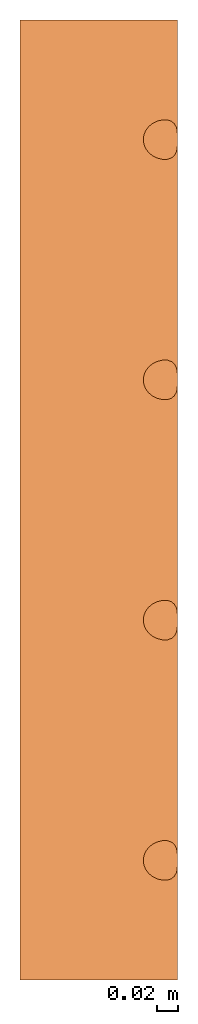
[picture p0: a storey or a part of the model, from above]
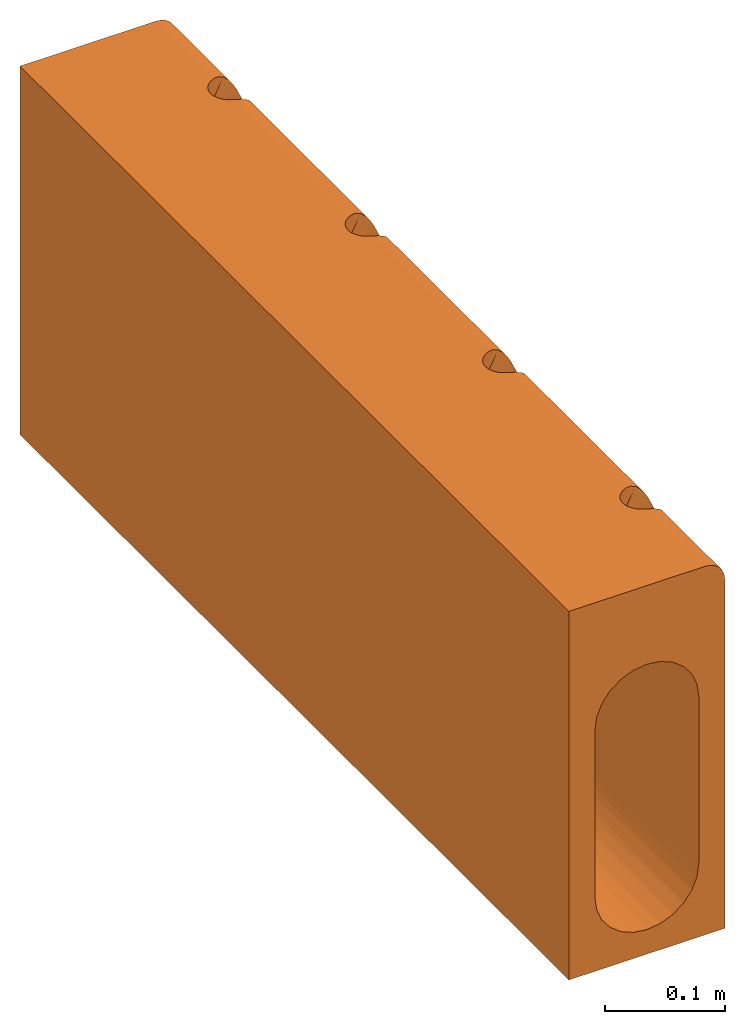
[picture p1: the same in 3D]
Properties of the parts of a building model (IFC2X3)

# File
Description: ViewDefinition [CoordinationView]
File name: 4983 - Perforated Centre Stone - 915mm LG.ifc
Time: 2013-09-18T16:28:03
Written by: Autodesk Revit 2013
Made in: 20120221_2030(x64)

# IfcProject, Project Number
LongName: Project Name; Phase: Project Status

# IfcSite, Default
RefLatitude: 42, 21, 30, 344238; RefLongitude: -71, -3, -35, -194702; RefElevation: 0 mm

# IfcBuilding
Pset_BuildingCommon - NumberOfStoreys: 2
Other - Project Status: Project Status; Project Issue Date: Issue Date; Project Address: Enter address here; Project Name: Project Name; Client Name: Owner; Project Number: Project Number

# IfcBuildingStorey (2)
Constraints - Elevation Base: 0
Graphics - Symbol: M_Level Head - Circle: M_Level Head - Circle; Color: 0; Symbol at End 2 Default: yes; Symbol at End 1 Default: no; Line Weight: 1; Line Pattern: Center
Identity Data - Structural: no; Building Story: yes
Dimensions - Computation Height: 0 mm
Name | LongName = Name | Elevation (mm) = Constraints, Elevation (mm)
T.O. Fnd. Wall | T.O. Fnd. Wall | -300
Level 1 | Level 1 | 0

# IfcBuildingElementProxy: 4983 - Perforated Centre Stone - 915mm LG, Civil-Drainage-Channel-ACO-KerbDrain-HB480(amar):4983 - Perforated Centre Stone - 915mm LG:4983 - Perforated Centre Stone - 915mm LG:481515
In: T.O. Fnd. Wall
Material: ACO Polymer Concrete.
Green Building Properties - End Cap Recycled Material Content: N/A; Access Cover/Frame Recycled Material Content: N/A; End Cap Recyclable: N/A; Channel Recycled Material Content: 20% minimum; Access Cover/Frame Recyclable: N/A; Channel Recyclable: Fully recyclable
Identity Data - Type Comments: ACO KerbDrain HB480 half battered perforated centre stone 25mm upstand 915mm long; Product Page URL: http://www.aco.co.uk/product_detail.php?id=3; Assembly Description: Rain Water Drainage; Maintenance guidelines: http://www.aco.co.uk/download.php?id=120; Product brochure: http://www.aco.co.uk/download.php?id=120; e-mail Technical: technical@aco.co.uk; e-mail Sales: customersupport@aco.co.uk; Model: ACO KerbDrain HB480; OmniClass Number: 23.70.50.24; Fax: +44 (0)1462 815895; Price: POA - contact ACO; URL: www.aco.co.uk www.aco.co.uk; Address: ACO Business Park, Hitchin Road, Shefford, Bedfordshire, United Kingdom SG17 5TE; Cost: 0; Manufacturer: ACO Technologies plc - ACO Water Management Division; OmniClass Title: Rainwater Removal; Telephone: +44 (0)1462 816666; Assembly Code: D2040; Product Code: 4983; Installation guidelines: http://www.aco.co.uk/download.php?id=120; Model Description: Combined kerb and drainage system
Dimensions - Volume: 28239786 mm3; Mitre Void End: -7995 mm; Void Depth: -355 mm; Void End I/O: 150 mm; Void Width: 150 mm; Mitre Void Start: -7987 mm; Junction Start: 0 mm; I/O endcap void depth: 2000 mm; Mitre Long end: 500 mm; Junction End: 150 mm; junction void depth: 2000 mm; Void Start I/O: 0 mm; Void Length: 915 mm; Mitre Small End: 487 mm; Straight Void Start: 0 mm
Phasing - Phase Created: Phase 1
Constraints - Moves With Nearby Elements: no; Level: Level: Level 1
Pset_BuildingElementProxyCommon - Reference: 4983 - Perforated Centre Stone - 915mm LG
Data - Product Weight: 59.7 Kg; Drainage Slot Width: 40mm; Product Standard: BS EN 1433:2002, CE marked, Kitemarked; Connection Pipe O.D: N/A; Channel C.S.A: 0.02mm²; Installation - Concrete Grade: Refer to brochure; Invert Depth: 350mm; Load Class: A 15 - D 400; ACO Hydraulic Design Software: http://www.acodesign.co.uk; Drainage Slot Intake area: 5026mm²/m; Product Dimensions: 915mm x 150mm x 375mm (LxWxH); Hydraulic Performance: http://www.aco.co.uk/download.php?id=120; Concrete Surround Volume - Load Class A 15 - D 400 - Grass or Asphalt Pavement: N/A; Concrete Surround Volume - Load Class A 15 - D 400 - Concrete Pavement: N/A
Construction - Junction access unit: no; 25-11m internal mitre: no; LH inlet/outlet end cap: no; RH drop kerb: no; Junction channel: no; Junction end cap: no; KDHB480 500_blindunit: no; cable loop: no; LH drop kerb: no; HB480-500: no; Bus stop kerb: no; Closing end cap: no; Centre Stone: no; RH inlet/outlet end cap: no; perforated centre stone: yes; Access Unit: no; 7-6m external mitre: no; LH BS transition kerb: no; RH BS transition kerb: no; 10-8m external mitre: no; 25-11m external mitre: no
Materials and Finishes - Access Cover/Frame Material: N/A; End Cap Material: N/A; Access Cover/Frame Colour: N/A; Access Cover/Frame Finish: N/A; End Cap Colour: N/A; Connection Pipe Material Colour: N/A; Connection Pipe Material: N/A; Channel Material: Vienite® Synthetic Resin Concrete; Channel Colour: Grey
General - TagNumber: 0.000000; SerialNumber: 0.000000
Other - Revision: 1; CreatedBy: www.aco.co.uk

# IfcOpeningElement: Opening (3)
In: Level 1
Constraints - Height Offset From Level: 0 mm; Related to Mass: no; Level: Level: Level 1; Room Bounding: yes
Dimensions - Volume: 2311976250 mm3; Thickness: 400 mm; Perimeter: 9790 mm; Area: 5901750 mm2
Structural - Structural: no; Enable Analytical Model: no
Phasing - Phase Created: Phase 1
Materials and Finishes - Structural Material: Earth
Construction - Default Thickness: 400 mm; Function: 0
Analytical Properties - Absorptance: 0.1; Thermal mass: 543920; Roughness: 1; Thermal Resistance (R): 0.477897; Heat Transfer Coefficient (U): 2.0925
Graphics - Coarse Scale Fill Color: 0

# IfcSlab: Floor:Generic Floor - 400mm, Floor:Generic Floor - 400mm:136426
In: Level 1
PredefinedType: FLOOR; Material: Earth 400 mm
Constraints - Height Offset From Level: 0 mm; Related to Mass: no; Level: Level: Level 1; Room Bounding: yes
Dimensions - Volume: 2311976250 mm3; Thickness: 400 mm; Perimeter: 9790 mm; Area: 5901750 mm2
Structural - Structural: no; Enable Analytical Model: no
Phasing - Phase Created: Phase 1
Pset_SlabCommon - Reference: Generic Floor - 400mm; IsExternal: no; LoadBearing: yes
Materials and Finishes - Structural Material: Earth
Construction - Default Thickness: 400 mm; Function: 0
Analytical Properties - Absorptance: 0.1; Thermal mass: 543920; Roughness: 1; Thermal Resistance (R): 0.477897; Heat Transfer Coefficient (U): 2.0925
Graphics - Coarse Scale Fill Color: 0
